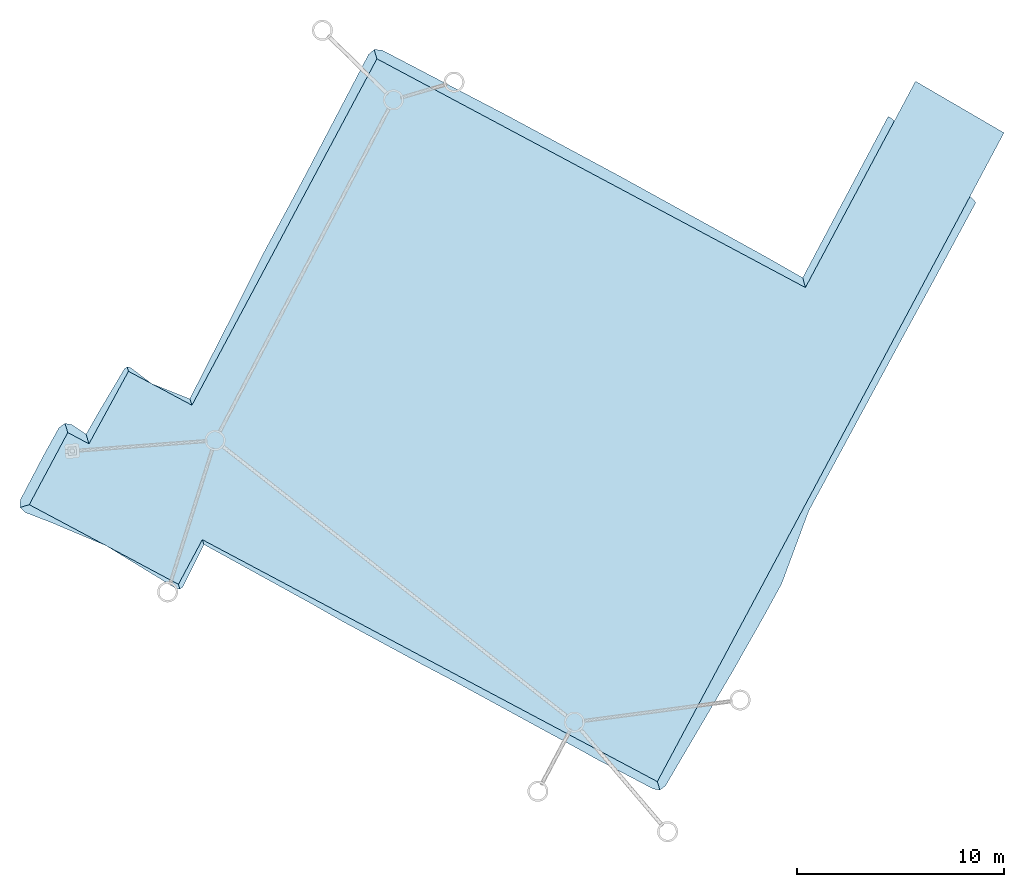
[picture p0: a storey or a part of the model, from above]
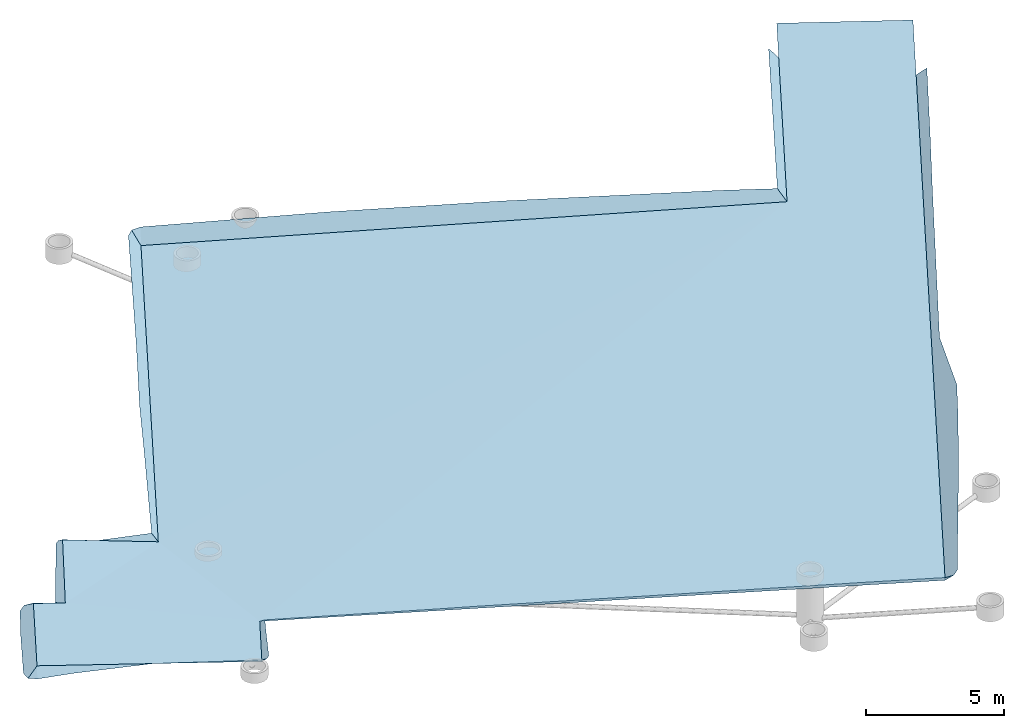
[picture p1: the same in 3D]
Properties of the parts of a building model (IFC2X3)

# File
Description: ViewDefinition [CoordinationView]
File name: Affaire2
Time: 2020-09-14T11:55:48
Made in: IfcPlusPlus

# IfcSite: Surface 3D (2)
PSET-MENSURA - Valeur décapage par défaut: 0 m
IfcElementQuantity - Valeur décapage par défaut: 0 m
Group: Surfaces 3D
Name | Description | Nom Surface MNT | PSET-MENSURA, Surface Horizontale (m2) = IfcElementQuantity, Surface Horizontale (m2) | PSET-MENSURA, Surface Selon la pente (m2) = IfcElementQuantity, Surface Selon la pente (m2)
Terrain | Surface 3D : Terrain | Terrain | 2255.51 | 2265.23
Terrain - Projet PTF | Surface 3D : Terrain - Projet PTF | Terrain - Projet PTF | 1427 | 1434.38

# IfcBuildingStorey, Extérieur (Terrain)
In: Non défini (Terrain)
Elevation: 87.02 m

# IfcFlowFitting: EU (10)
In: Extérieur (Terrain)
Description: Reseaux EU; Group: Reseaux EU; EU
PSET-MENSURA - Catalogue Fourniture: Bdd noeuds GENIUS; Hauteur Element de fond: 0 m; Hauteur de décantation: 0 m; URL: http://
IfcElementQuantity - Hauteur Element de fond: 0 m; Hauteur de décantation: 0 m
Name (Noeud :...) | Numéro | Type de regard | X (m) | Y (m) | Z tampon (m) | Zfe 1 (m) | PSET-MENSURA, Profondeur (m) = IfcElementQuantity, Profondeur (m)
 R2 | R2 | 1.Visite | -68.964 | -41.7479 | 172.49 | 170.5 | 2.08979 | PSET-MENSURA - Zfe 2: 170.5 m; Zfe 3: 170.5 m; Zfe 4: 170.5 m
 R1 | R1 | 1.Visite | -60.3494 | -25.2907 | 172.597 | 170.4 | 2.29714 | PSET-MENSURA - Zfe 2: 170.4 m; Zfe 3: 170.4 m
 R3 | R3 | 1.Visite | -51.5994 | -55.3674 | 173.759 | 171.6 | 2.25924 | PSET-MENSURA - Zfe 2: 171.6 m; Zfe 3: 171.6 m; Zfe 4: 171.6 m
 R4 | R4 | 1.Visite | -47.0976 | -60.6597 | 174.023 | 173.5 | 0.623164
 R5 | R5 | 1.Visite | -53.3666 | -58.7091 | 173.724 | 173.2 | 0.624432
 R6 | R6 | 1.Visite | -71.2634 | -49.0741 | 172.538 | 172.2 | 0.438329
 R7 | R7 | 2.Brancht | -75.8722 | -42.2633 | 172.067 | 171.57 | 0.596955
 R8 | R8 | 1.Visite | -57.419 | -24.4324 | 172.748 | 172.25 | 0.597632
 R9 | R9 | 1.Visite | -63.7792 | -21.9281 | 172.279 | 171.7 | 0.678681
 R10 | R10 | 1.Visite | -43.5906 | -54.2984 | 174.235 | 173.7 | 0.63518

# IfcFlowSegment: EU (9)
In: Extérieur (Terrain)
Description: Reseaux EU; Group: Reseaux EU; EU
PSET-MENSURA - Type de réseaux: EU; Type Collecteur: Circulaire; Diamètre de référence (mm): 200 mm; Diamètre intérieur: 183 mm; Epaisseur collecteur: 0.0085 m; Longueur utile: 6 m; Longueur Hors tout: 0 m; Poids (kg): 0 kg; Diamètre Forage: 0 mm; Rugosité : Coef de Bazin: 0.06; Rugosité : Coef Manning Stickler: 90; Rugosité : Coef Colebrook White: 0.54; Surface de référence: Aucune; Fouille: Aucune; Référence imposée: Non; Tronçon existant: Non
IfcElementQuantity - Epaisseur collecteur: 0.0085 m; Longueur utile: 6 m; Longueur Hors tout: 0 m; Poids (kg): 0 kg
Name (Tronçon :...) | Regard/Noeud Amont | Regard/Noeud Aval | Gamme | PSET-MENSURA, Longeur tronçon (m) = IfcElementQuantity, Longeur tronçon (m) | Pente %
 R2 - R1 | R2 | R1 | PVC CR8 EU | 18.5758 | 0.538343
 R3 - R2 | R3 | R2 | PVC CR8 EU | 22.0959 | 4.98447
 R4 - R3 | R4 | R3 | PVC CR8 EP | 7.20307 | 27.3462
 R5 - R3 | R5 | R3 | PVC CR8 EU | 4.10495 | 42.3247
 R6 - R2 | R6 | R2 | PVC CR8 EP | 7.86458 | 22.1393
 R7 - R2 | R7 | R2 | PVC CR8 EP | 7.00954 | 15.4459
 R8 - R1 | R8 | R1 | PVC CR8 EU | 3.57019 | 60.5865
 R9 - R1 | R9 | R1 | PVC CR8 EU | 4.97597 | 27.0656
 R10 - R3 | R10 | R3 | PVC CR8 EU | 8.34826 | 25.9907

# IfcFurnishingElement: Objet 3D, [ manhole 010 ]
In: Extérieur (Terrain)
Description: Bibliothèque Mensura / Regards tampons; Group: Objets 3D
PSET-MENSURA - X: -75.8722 m; Y: -42.2633 m; Z: 172.067 m
PSET - Attributs Mensura - Dimension: 70x70

# IfcGroup (13)
Name | Group
Terrains
Terrain | Terrains
Surfaces 3D | Terrain
Projets Plates-formes
Projet PTF | Projets Plates-formes
Surfaces 3D | Projet PTF
Couches Structure PTF | Projet PTF
Surfaces 3D | Couches Structure PTF
Terrain - Projet PTF | Terrains
Surfaces 3D | Terrain - Projet PTF
Réseaux d'assainissement
Reseaux EU | Réseaux d'assainissement
Objets 3D

# IfcSlab: Défaut (3)
In: Extérieur (Terrain)
Description: Défaut | Ptf : 1; Group: Surfaces 3D
PSET-MENSURA - Numéro de PTF: 1; Code de PTF: Défaut
Name (Ptf :...) | PSET-MENSURA, Surface Horizontale (m2) = IfcElementQuantity, Surface Horizontale (m2) | PSET-MENSURA, Surface Selon la pente (m2) = IfcElementQuantity, Surface Selon la pente (m2) | PSET-MENSURA, Volume Déblais (m3) = IfcElementQuantity, Volume Déblais (m3) | PSET-MENSURA, Volume Remblais (m3) = IfcElementQuantity, Volume Remblais (m3) | PSET-MENSURA, Epaisseur Décaissement (m) = IfcElementQuantity, Epaisseur Décaissement (m)
 1 | 51.0722 | 71.261 | 10.3173 | 0.557551
 1 | 791.459 | 792.486 | 295.314 | 2.95017 | 0
 1 | 791.459 | 792.486 | 295.314 | 2.95017 | 0 | Material: Décaissement 0 m
